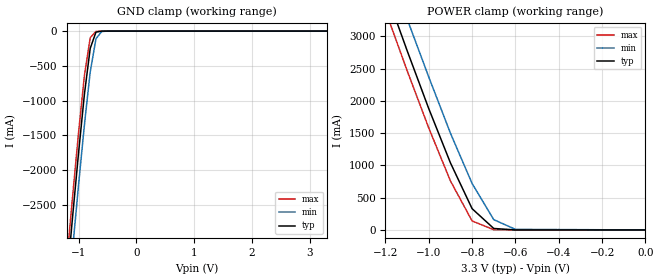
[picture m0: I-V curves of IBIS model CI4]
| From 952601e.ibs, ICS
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|   Model CI4
[Model]   CI4
Model_type   Input
Polarity   Inverting
Vinl =   0.80V
Vinh =   2.00V
C_comp   5.50pF   5.00pF   6.00pF
[Temperature Range]   27.00   70.00   0.000
[Voltage Range]   3.30V   3.00V   3.70V
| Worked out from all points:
|   GND clamp passes 1 mA (typ) near -0.60 V on its own axis
|   POWER clamp passes 1 mA (typ) near -0.60 V on its own axis
[GND_clamp]
| voltage   I(typ)   I(min)   I(max)
-3.3V     -24.05A    -24.49A    -23.79A
-1.2V     -3.55A     -4.02A     -3.26A
-1.1V     -2.63A     -3.1A      -2.34A
-1V       -1.74A     -2.2A      -1.45A
-900mV    -910mA     -1.35A     -640mA
-800mV    -250mA     -590mA     -96.82mA
-700mV    -14.58mA   -110mA     -3.87mA
-600mV    -880uA     -5.84mA    -450uA
-500mV    -88.5uA    -350uA     -45.09uA
3.3V      130pA      470nA      90.8pA
[POWER_clamp]
| voltage   I(typ)   I(min)   I(max)
-3.3V     24.22A     24.67A     23.94A
-1.2V     3.71A      4.2A       3.4A
-1.1V     2.78A      3.27A      2.47A
-1V       1.88A      2.37A      1.58A
-900mV    1.04A      1.5A       760mA
-800mV    330mA      720mA      140mA
-700mV    23.1mA     160mA      3.86mA
-600mV    560uA      9.41mA     65.29uA
0V        130pA      310pA      130pA
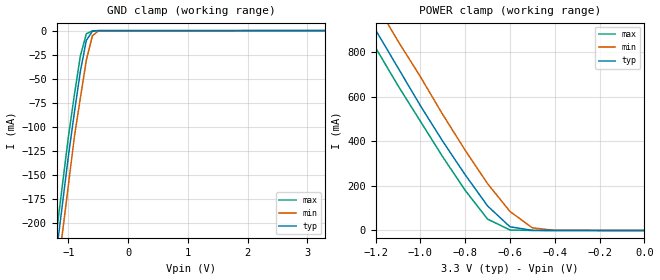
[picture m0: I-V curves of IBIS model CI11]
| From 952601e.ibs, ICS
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|   Model CI11
[Model]   CI11
Model_type   Input
Polarity   Non-Inverting
Vinl = 800.00mV
Vinh =   2.00V
C_comp   5.50pF   5.00pF   6.00pF
[Temperature Range]   27.00   70.00   0.000
[Voltage Range]   3.30V   3.00V   3.70V
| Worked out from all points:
|   GND clamp passes 1 mA (typ) near -0.60 V on its own axis
|   POWER clamp passes 1 mA (typ) near -0.50 V on its own axis
[GND_clamp]
| voltage   I(typ)   I(min)   I(max)
-3.3V     -1.3A      -1.33A     -1.29A
-1.2V     -230mA     -260mA     -210mA
-1.1V     -180mA     -210mA     -160mA
-1V       -130mA     -160mA     -110mA
-900mV    -84.66mA   -110mA     -66.41mA
-800mV    -42.01mA   -69.77mA   -26.07mA
-700mV    -10.04mA   -30.44mA   -3.27mA
-600mV    -710uA     -5.48mA    -280uA
-500mV    -47.65uA   -330uA     -21.63uA
3.3V      68.36pA    16.98uA    46.98pA
[POWER_clamp]
| voltage   I(typ)   I(min)   I(max)
-3.3V     4.55A      4.67A      4.48A
-1.3V     1.07A      1.19A      990mA
-1.2V     900mA      1.02A      820mA
-1.1V     730mA      850mA      650mA
-1V       560mA      690mA      490mA
-900mV    400mA      520mA      330mA
-800mV    250mA      360mA      180mA
-700mV    110mA      210mA      50.94mA
-600mV    16.55mA    85.28mA    2.33mA
-500mV    490uA      11.75mA    35.16uA
-400mV    10.4uA     490uA      500nA
0V        68.36pA    140pA      74.21pA
